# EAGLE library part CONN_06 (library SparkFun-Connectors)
Multi connection point. Often used as Generic Header-pin footprint for 0.1 inch spaced/style header connections On any of the 0.1 inch spaced packages, you can populate with these: Break Away Headers - Straight (PRT-00116) Break Away Male Headers - Right Angle (PRT-00553) Female Headers (PRT-00115) Break Away Headers - Machine Pin (PRT-00117) Break Away Female Headers - Swiss Machine Pin (PRT-00743) Arduino Stackable Header - 6 Pin (PRT-09280) Screw Terminals 2.54mm Pitch (6-Pin) (PRT-16499) For SCREWTERMINALS and SPRING TERMINALS visit here: Screw Terimnals on SparkFun.com (5mm/3.5mm/2.54mm spacing) This device is also useful as a general connection point to wire up your design to another part of your project. Our various solder wires solder well into these plated through hole pads. Hook-Up Wire - Assortment (Stranded, 22 AWG) (PRT-11375) Hook-Up Wire - Assortment (Solid Core, 22 AWG) (PRT-11367) View the entire wire category on our website here

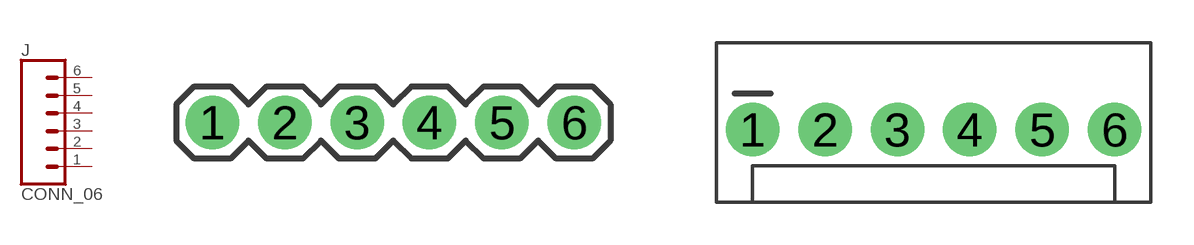
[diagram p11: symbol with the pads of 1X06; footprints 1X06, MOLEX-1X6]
Designator prefix J

## CONN_06SILK_FEMALE_PTH (PROD_ID: CONN-08437)  [1X06]
1  1  pas
2  2  pas
3  3  pas
4  4  pas
5  5  pas
6  6  pas

## CONN_06POLAR  [MOLEX-1X6]
Pads as for 1X06

## CONN_06RA  [MOLEX-1X6-RA]
Pads as for 1X06

## CONN_06SMD (PROD_ID: CONN-08971; VALUE: RA 6Pin SMD)  [1X06-SMD_RA_MALE]
Pads as for 1X06

## CONN_06LOCK  [1X06_LOCK]
Pads as for 1X06

## CONN_06LOCK_LONGPADS  [1X06_LOCK_LONGPADS]
Pads as for 1X06

## CONN_06POLAR_LOCK  [MOLEX-1X6_LOCK]
Pads as for 1X06

## CONN_06RA_LOCK  [MOLEX_1X6_RA_LOCK]
Pads as for 1X06

## CONN_06FEMALE_LOCK  [1X06_FEMALE_LOCK.010]
Pads as for 1X06

## CONN_06LONGPADS  [1X06_LONGPADS]
Pads as for 1X06

## CONN_063.5MM-6 (PROD_ID: CONN-13617)  [SCREWTERMINAL-3.5MM-6]
Pads as for 1X06

## CONN_06SMD-FEMALE-V2 (PROD_ID: CONN-09668)  [1X06-SMD-FEMALE]
Pads as for 1X06

## CONN_06POGOPIN_HOLES_ONLY (PROD_ID: CONN-08437)  [1X06_HOLES_ONLY]
Pads as for 1X06

## CONN_06SMD-STRAIGHT-FEMALE (PROD_ID: CONN-10203)  [1X06_SMD_STRAIGHT]
Pads as for 1X06

## CONN_06SMD-STRAIGHT-ALT-FEMALE (PROD_ID: CONN-10203)  [1X06_SMD_STRAIGHT_ALT]
Pads as for 1X06

## CONN_06SMD-STRAIGHT-COMBO-FEMALE (PROD_ID: CONN-10203)  [1X06_SMD_STRAIGHT_COMBO]
Pads as for 1X06

## CONN_06SMD_MALE (PROD_ID: CONN-11293)  [1X06_SMD_MALE]
Pads as for 1X06

## CONN_06SMD-1MM (PROD_ID: CONN-08249; SF_ID: GPS-00579)  [1X06-1MM]
Pads as for 1X06

## CONN_06NO_SILK_FEMALE_PTH (PROD_ID: CONN-08437)  [1X06_NO_SILK]
Pads as for 1X06

## CONN_061.27MM  [1X06_1.27MM]
Pads as for 1X06

## CONN_06NO_SILK_NO_POP  [1X06_NO_SILK]
Pads as for 1X06

## CONN_062.5MM-6-90  [1X06_SCREW_TERMINAL_BLOCK]
Pads as for 1X06

## CONN_06JST-SMD-LOCKING (PROD_ID: CONN-16497)  [JST-6-SMD-1.25MM-LOCKING]
Pads as for 1X06

## CONN_061MM-LIF (PROD_ID: CONN-16692)  [FPC_6_1MM-LIF]
Pads as for 1X06

## CONN_062.54MM_SCREW_TERMINALS (PROD_ID: CONN-14885)  [1X06_2.54MM_SCREWPIN]
Pads as for 1X06

## CONN_06PAD  [1X06_SOLDER_PADS]
Pads as for 1X06

## Footprint 1X06 (pad centres in mm)
Plated Through Hole - 6 Pin Specifications: Pin count:6 Pin pitch:0.1" Example device(s): CONN_06
drill 1.016 pad 1.88: 1 0,0; 2 2.54,0; 3 5.08,0; 4 7.62,0; 5 10.16,0; 6 12.7,0

## Footprint MOLEX-1X6 (pad centres in mm)
Molex 6-Pin Plated Through-Hole Specifications: Pin count:6 Pin pitch:0.1" Datasheet referenced for footprint Example device(s): CONN_06
drill 1.016 pad 1.88: 1 0,0; 2 2.54,0; 3 5.08,0; 4 7.62,0; 5 10.16,0; 6 12.7,0

## Footprint MOLEX-1X6-RA (pad centres in mm)
Molex 6-Pin Plated Through-Hole Right Angle tPlace shows angle of connector. Specifications: Pin count:6 Pin pitch:0.1" Datasheet referenced for footprint Example device(s): CONN_06
drill 1.016 pad 1.88: 1 0,0; 2 2.54,0; 3 5.08,0; 4 7.62,0; 5 10.16,0; 6 12.7,0

## Footprint 1X06-SMD_RA_MALE (pad centres in mm)
SMD - 6 Pin Right Angle Male Header tDocu layer shows pin locations. Specifications: Pin count:6 Pin pitch:0.1" Example device(s): CONN_06
smd 1 x 3: 1 -6.35,5; 2 -3.81,5; 3 -1.27,5; 4 1.27,5; 5 3.81,5; 6 6.35,5
hole 1.4 at -5.08,0
hole 1.4 at 5.08,0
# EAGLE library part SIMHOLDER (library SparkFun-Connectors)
SIM Cellular Card Socket SMT 6 pin standard connection. SparkFun Products: SIM Socket SparkFun Cellular Shield - MG2639 SparkFun SIM Card Socket Breakout

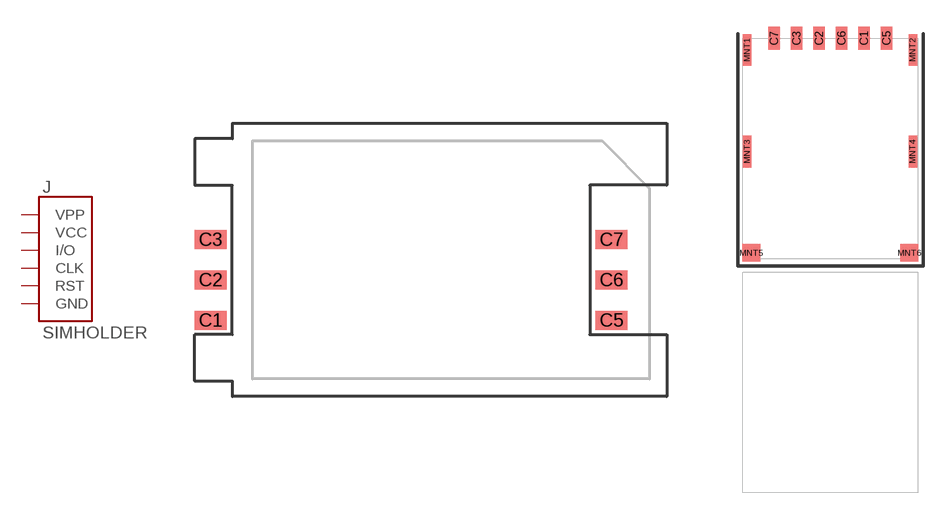
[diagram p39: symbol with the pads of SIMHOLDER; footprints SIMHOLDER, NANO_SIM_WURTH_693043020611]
Designator prefix J

## SIMHOLDER-SIM (PROD_ID: CONN-08536; SF_ID: PRT-00548)  [SIMHOLDER]
C1  VCC  pwr
C2  RST  in
C3  CLK  in
C5  GND  pwr
C6  VPP  in
C7  I/O

## SIMHOLDER-NANOSIM (PROD_ID: CONN-14097)  [NANO_SIM_WURTH_693043020611]
Pads as for SIMHOLDER

## SIMHOLDER-NANOSIM-MOLEX (PROD_ID: CONN-15682)  [NANO_SIM_MOLEX_104224-0820]
G1  GND  pwr
G2  GND  pwr
G3  GND  pwr
G4  GND  pwr
S1  VCC  pwr
S2  RST  in
S3  CLK  in
S4  GND  pwr
S5  VPP  in
S6  I/O

## SIMHOLDER-PUSHPUSH (PROD_ID: CONN-16272)  [NANO_SIM_PP]
Pads as for SIMHOLDER

## SIMHOLDER-PUSHPUSH-REDUCED-PADS (PROD_ID: CONN-16272)  [NANO_SIM_PP_REDUCED_PADS]
Pads as for SIMHOLDER

## Footprint SIMHOLDER (pad centres in mm)
SIM Card Socket SMT Specifications: Pin count: 6 Pin pitch:2.54mm Datasheet referenced for footprint Example device(s): SIMHOLDER
smd 2 x 1.2: C1 -12.61,-3.81; C2 -12.61,-1.27; C3 -12.61,1.27; C5 12.61,-3.81; C6 12.61,-1.27; C7 12.61,1.27

## Footprint NANO_SIM_WURTH_693043020611 (pad centres in mm)
Wurth Nano-SIM Holder &ndash; 693043020611 Datasheet
smd 0.65 x 1.3: C1 1.905,6.25; C2 -0.635,6.25; C3 -1.905,6.25; C5 3.175,6.25; C6 0.635,6.25; C7 -3.175,6.25
smd 0.48 x 1.8: MNT1 -4.69,5.58; MNT2 4.66,5.58; MNT3 -4.69,-0.17; MNT4 4.66,-0.17
smd 1.03 x 1: MNT5 -4.465,-5.89; MNT6 4.465,-5.89

## Footprint NANO_SIM_MOLEX_104224-0820 (pad centres in mm)
Molex Nano-SIM Holder &ndash; 1042240820 Datasheet
smd 1 x 2.3: G1 -5.1,1.5; G2 -5.1,8.7; G3 5.1,8.7; G4 5.1,1.5
smd 1.1 x 1: R1 -1.82,12.625; R2 1.82,12.625
smd 1 x 0.8: S1 4.9,4.35; S2 4.9,5.55; S3 -4.9,4.35; S4 4.9,6.75; S5 -4.9,5.55; S6 -4.9,6.75

## Footprint NANO_SIM_PP (pad centres in mm)
Part#: ATOM-A03621 or MUP-C7801
smd 0.7 x 2.1: A1 6.495,6; A2 -6.495,6; A3 -6.495,-6; A4 6.495,-6
smd 0.65 x 1.23: C1 0.255,7.535; C2 -2.285,7.535; C3 -4.825,7.535; C5 1.525,7.535; C6 -1.015,7.535; C7 -3.555,7.535; CD 2.475,7.535
hole 0.75 at 3.505,-4.75
hole 0.75 at -4.995,-4.75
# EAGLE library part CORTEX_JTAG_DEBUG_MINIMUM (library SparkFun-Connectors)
Cortex Debug Connector - 10 pin Supports JTAG debug, Serial Wire debug, and Serial Wire Viewer. PTH and SMD connector options available. General Connector Information Products: PTH Connector -via Digi-Key SparkFun PSoc SparkFun T

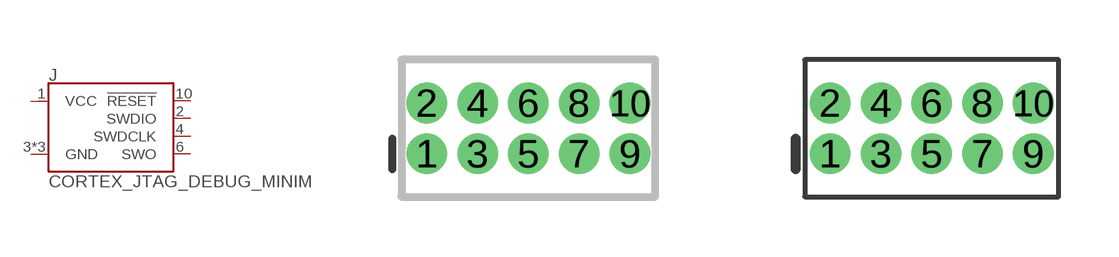
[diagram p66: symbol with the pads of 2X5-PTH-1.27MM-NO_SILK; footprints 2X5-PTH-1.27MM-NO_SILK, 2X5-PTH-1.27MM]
Designator prefix J

## CORTEX_JTAG_DEBUG_MINIMUM_PTH_NS  [2X5-PTH-1.27MM-NO_SILK]
1  VCC
2  SWDIO
3  GND
4  SWDCLK
5  GND
6  SWO
9  GND
10  !RESET

## CORTEX_JTAG_DEBUG_MINIMUM_PTH  [2X5-PTH-1.27MM]
Pads as for 2X5-PTH-1.27MM-NO_SILK

## CORTEX_JTAG_DEBUG_MINIMUM_SMD (PROD_ID: CONN-14503)  [2X5-SMD-1.27MM]
Pads as for 2X5-PTH-1.27MM-NO_SILK

## CORTEX_JTAG_DEBUG_MINIMUM_SMD-UNSHROUDED (PROD_ID: CONN-15353)  [2X5-SMD-UNSHROUDED]
Pads as for 2X5-PTH-1.27MM-NO_SILK

## CORTEX_JTAG_DEBUG_MINIMUM_SMD_UNSHROUDED_DNP_NO_PASTE  [2X5-SMD-UNSHROUDED_DNP_NO_PASTE]
Pads as for 2X5-PTH-1.27MM-NO_SILK

## Footprint 2X5-PTH-1.27MM-NO_SILK (pad centres in mm)
Plated Through Hole - 2x5 ARM Cortex Debug Connector (10-pin) tDoc (51) layer border represents maximum dimensions of plastic housing. Specifications: Pin count:10 Pin pitch:1.27mm Datasheet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
drill 0.508 pad 1: 1 -2.54,-0.635; 2 -2.54,0.635; 3 -1.27,-0.635; 4 -1.27,0.635; 5 0,-0.635; 6 0,0.635; 7 1.27,-0.635; 8 1.27,0.635; 9 2.54,-0.635; 10 2.54,0.635

## Footprint 2X5-PTH-1.27MM (pad centres in mm)
Plated Through Hole - 2x5 ARM Cortex Debug Connector (10-pin) tDoc (51) layer border represents maximum dimensions of plastic housing. Specifications: Pin count:10 Pin pitch:1.27mm Datasheet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
drill 0.508 pad 1: 1 -2.54,-0.635; 2 -2.54,0.635; 3 -1.27,-0.635; 4 -1.27,0.635; 5 0,-0.635; 6 0,0.635; 7 1.27,-0.635; 8 1.27,0.635; 9 2.54,-0.635; 10 2.54,0.635

## Footprint 2X5-SMD-1.27MM (pad centres in mm)
Shrouded SMD connector for JTAG and SWD applications.
smd 0.76 x 2.4: 1 2.54,1.95; 2 2.54,-1.95; 3 1.27,1.95; 4 1.27,-1.95; 5 0,1.95; 6 0,-1.95; 7 -1.27,1.95; 8 -1.27,-1.95; 9 -2.54,1.95; 10 -2.54,-1.95

## Footprint 2X5-SMD-UNSHROUDED (pad centres in mm)
SMD - 2x5 Unshrouded ARM Cortex Debug Connector (10-pin) Specifications: Pin count:10 Pin pitch:1.27mm Datasheet referenced for footprint
smd 0.74 x 2.38: 1 -2.54,-1.88; 2 -2.54,1.88; 3 -1.27,-1.88; 4 -1.27,1.88; 5 0,-1.88; 6 0,1.88; 7 1.27,-1.88; 8 1.27,1.88; 9 2.54,-1.88; 10 2.54,1.88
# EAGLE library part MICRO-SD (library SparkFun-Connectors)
microSD Socket for Transflash Various sockets for µSD. tDoc lines correctly indicate media card edge positions when inserting (unlocked, locked, depressed). NOTE: CD1 and CD2 are connected internally, and the default detect state of the socket is detect pin to ground. SparkFun Products: WAV Trigger CAN-Bus Shield SparkFun Level Shifing microSD Breakout

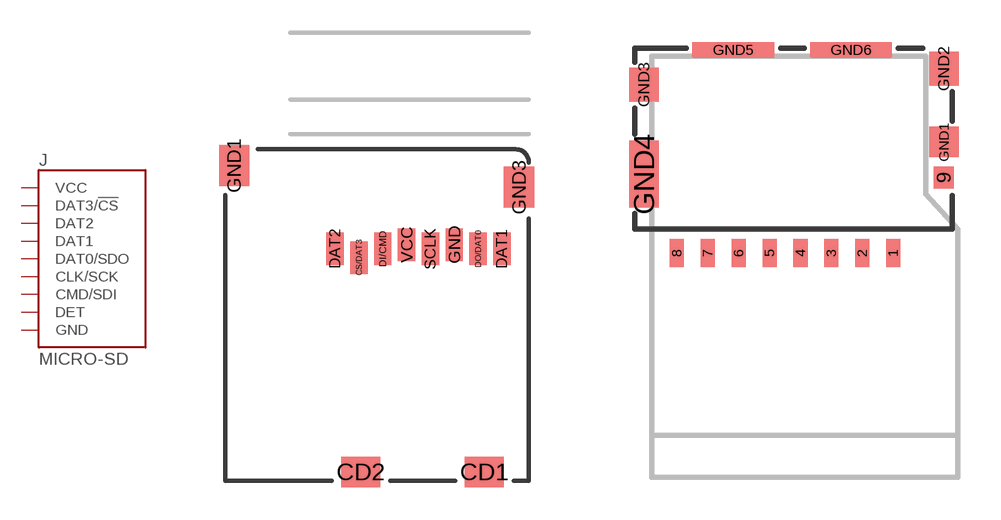
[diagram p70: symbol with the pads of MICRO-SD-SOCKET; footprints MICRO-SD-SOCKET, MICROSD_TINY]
Designator prefix J

## MICRO-SDPUSH-PUSH (PROD_ID: CONN-07820)  [MICRO-SD-SOCKET]
CD1  DET
CS/DAT3  DAT3/!CS!
DAT1  DAT1
DAT2  DAT2
DI/CMD  CMD/SDI
DO/DAT0  DAT0/SDO
GND  GND
GND1  GND
GND3  GND
SCLK  CLK/SCK
VCC  VCC

## MICRO-SDFRICTION (PROD_ID: CONN-13500)  [MICROSD_TINY]
1  DAT2
2  DAT3/!CS!
3  CMD/SDI
4  VCC
5  CLK/SCK
6  GND
7  DAT0/SDO
8  DAT1
9  DET
GND1  GND
GND2  GND
GND3  GND
GND4  GND
GND5  GND
GND6  GND

## MICRO-SD-PUSH-PUSH-EXT-PIN (PROD_ID: CONN-16110)  [MICROSD-EXTERNALPIN]
1  DAT2
2  DAT3/!CS!
3  CMD/SDI
4  VCC
5  CLK/SCK
6  GND
7  DAT0/SDO
8  DAT1
9  DET
10  GND
11  GND
12  GND
13  GND

## Footprint MICRO-SD-SOCKET (pad centres in mm)
microSD Socket SMD Puhs-Push type. tDocu shows location of uSD card in different positions. Specifications: Pin count:12 Datasheet referenced for footprint Example device(s): MICRO-SD_CARD_SOCKET
smd 1.8 x 1.4: CD1 -2.05,0.4; CD2 -7.75,0.4
smd 0.8 x 1.5: CS/DAT3 -7.84,10.3; DAT1 -1.24,10.7; DAT2 -8.94,10.7; DI/CMD -6.74,10.7; DO/DAT0 -2.34,10.7; GND -3.44,10.9; SCLK -4.54,10.7; VCC -5.64,10.9
smd 1.4 x 1.9: GND1 -13.6,14.55; GND3 -0.45,13.55

## Footprint MICROSD_TINY (pad centres in mm)
smd 0.5 x 1: 1 3.55,-3.85; 2 2.45,-3.85; 3 1.35,-3.85; 4 0.25,-3.85; 5 -0.85,-3.85; 6 -1.95,-3.85; 7 -3.05,-3.85; 8 -4.15,-3.85
smd 0.72 x 0.78: 9 5.35,-1.17
smd 1.05 x 1.08: GND1 5.35,0.1
smd 1.05 x 1.2: GND2 5.35,2.71; GND3 -5.325,2.14
smd 1.05 x 2.39: GND4 -5.325,-1.045
smd 2.91 x 0.55: GND5 -2.145,3.385; GND6 2.045,3.385

## Footprint MICROSD-EXTERNALPIN (pad centres in mm)
smd 0.7 x 1.6: 1 2.25,10.5; 2 1.15,10.5; 3 0.05,10.5; 4 -1.05,10.5; 5 -2.15,10.5; 6 -3.25,10.5; 7 -4.35,10.5; 8 -5.45,10.5; 9 -6.55,10.5
smd 1.2 x 1.6: 10 -7.75,9.9
smd 1.2 x 2.2: 11 -7.75,0.4; 12 7.75,0.4
smd 1.6 x 1.4: 13 6.85,10
hole 1 at 3.05,0
hole 1 at -4.95,0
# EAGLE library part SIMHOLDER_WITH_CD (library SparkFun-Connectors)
SIM Cellular Card Socket SMT 6 pin standard connection. SparkFun Products: SIM Socket SparkFun Cellular Shield - MG2639 SparkFun SIM Card Socket Breakout

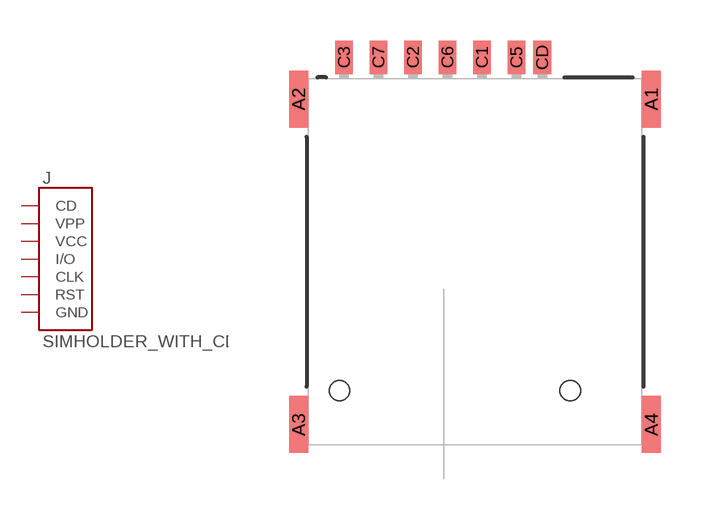
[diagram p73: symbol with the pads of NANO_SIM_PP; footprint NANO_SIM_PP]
Designator prefix J

## SIMHOLDER_WITH_CD-PUSHPUSH (PROD_ID: CONN-16272; VALUE: NANO_SIM)  [NANO_SIM_PP]
A1  GND  pwr
A2  GND  pwr
A3  GND  pwr
A4  GND  pwr
C1  VCC  pwr
C2  RST  in
C3  CLK  in
C5  GND  pwr
C6  VPP  in
C7  I/O
CD  CD  in

## Footprint NANO_SIM_PP (pad centres in mm)
Part#: ATOM-A03621 or MUP-C7801
smd 0.7 x 2.1: A1 6.495,6; A2 -6.495,6; A3 -6.495,-6; A4 6.495,-6
smd 0.65 x 1.23: C1 0.255,7.535; C2 -2.285,7.535; C3 -4.825,7.535; C5 1.525,7.535; C6 -1.015,7.535; C7 -3.555,7.535; CD 2.475,7.535
hole 0.75 at 3.505,-4.75
hole 0.75 at -4.995,-4.75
